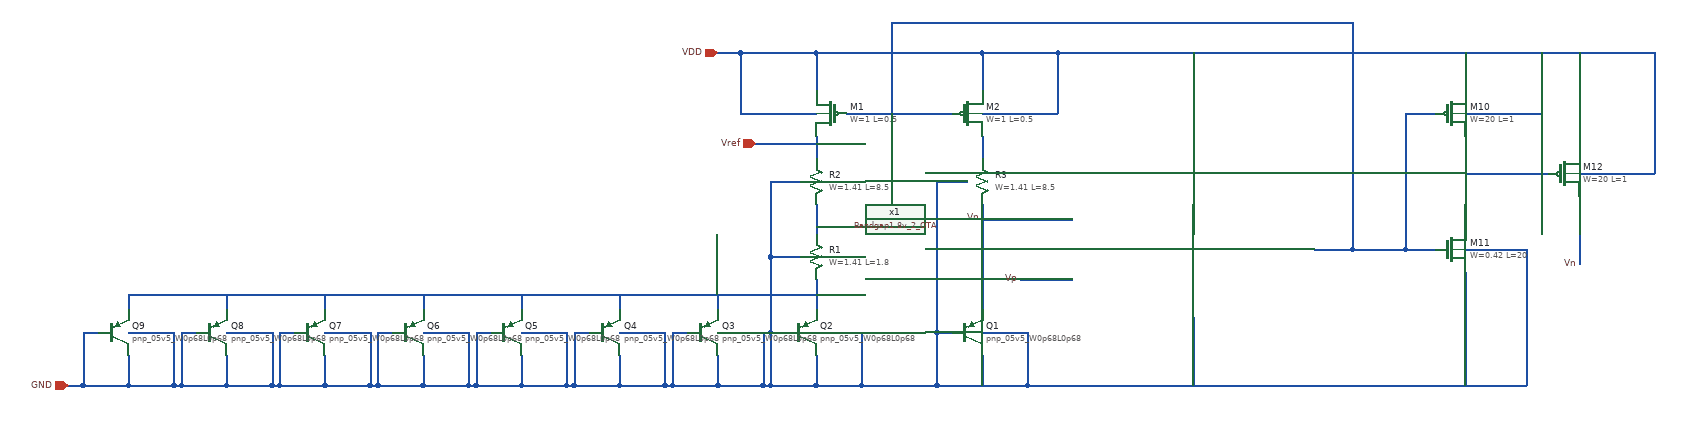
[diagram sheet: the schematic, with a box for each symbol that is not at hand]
v {xschem version=2.9.9 file_version=1.2 }
G {}
K {}
V {}
S {}
E {}
N -1770 -1250 -1630 -1250 { lab=#net1}
N -1590 -1330 -1590 -1280 { lab=VDD}
N -1810 -1330 -1590 -1330 { lab=VDD}
N -1810 -1330 -1810 -1280 { lab=VDD}
N -1590 -1250 -1490 -1250 { lab=VDD}
N -1490 -1330 -1490 -1250 { lab=VDD}
N -1590 -1330 -1490 -1330 { lab=VDD}
N -1910 -1250 -1810 -1250 { lab=VDD}
N -1910 -1330 -1910 -1250 { lab=VDD}
N -1910 -1330 -1810 -1330 { lab=VDD}
N -1590 -1220 -1590 -1190 { lab=#net2}
N -1810 -1220 -1810 -1190 { lab=xxx}
N -1810 -1130 -1810 -1090 { lab=Vp}
N -1590 -1130 -1590 -990 { lab=Vn}
N -1810 -1030 -1810 -990 { lab=#net3}
N -1590 -930 -1590 -890 { lab=GND}
N -1590 -960 -1530 -960 { lab=GND}
N -1530 -960 -1530 -890 { lab=GND}
N -1650 -960 -1630 -960 { lab=GND}
N -1650 -960 -1650 -890 { lab=GND}
N -1650 -890 -1530 -890 { lab=GND}
N -1810 -930 -1810 -890 { lab=GND}
N -1810 -890 -1750 -890 { lab=GND}
N -1750 -960 -1750 -890 { lab=GND}
N -1810 -960 -1750 -960 { lab=GND}
N -1870 -960 -1850 -960 { lab=GND}
N -1870 -960 -1870 -890 { lab=GND}
N -1870 -890 -1810 -890 { lab=GND}
N -1940 -930 -1940 -890 { lab=GND}
N -1940 -890 -1880 -890 { lab=GND}
N -1880 -960 -1880 -890 { lab=GND}
N -1940 -960 -1880 -960 { lab=GND}
N -2000 -960 -1980 -960 { lab=GND}
N -2000 -960 -2000 -890 { lab=GND}
N -2000 -890 -1940 -890 { lab=GND}
N -2070 -930 -2070 -890 { lab=GND}
N -2070 -890 -2010 -890 { lab=GND}
N -2010 -960 -2010 -890 { lab=GND}
N -2070 -960 -2010 -960 { lab=GND}
N -2130 -960 -2110 -960 { lab=GND}
N -2130 -960 -2130 -890 { lab=GND}
N -2130 -890 -2070 -890 { lab=GND}
N -2200 -930 -2200 -890 { lab=GND}
N -2200 -890 -2140 -890 { lab=GND}
N -2140 -960 -2140 -890 { lab=GND}
N -2200 -960 -2140 -960 { lab=GND}
N -2260 -960 -2240 -960 { lab=GND}
N -2260 -960 -2260 -890 { lab=GND}
N -2260 -890 -2200 -890 { lab=GND}
N -2330 -930 -2330 -890 { lab=GND}
N -2330 -890 -2270 -890 { lab=GND}
N -2270 -960 -2270 -890 { lab=GND}
N -2330 -960 -2270 -960 { lab=GND}
N -2390 -960 -2370 -960 { lab=GND}
N -2390 -960 -2390 -890 { lab=GND}
N -2390 -890 -2330 -890 { lab=GND}
N -2460 -930 -2460 -890 { lab=GND}
N -2460 -890 -2400 -890 { lab=GND}
N -2400 -960 -2400 -890 { lab=GND}
N -2460 -960 -2400 -960 { lab=GND}
N -2520 -960 -2500 -960 { lab=GND}
N -2520 -960 -2520 -890 { lab=GND}
N -2520 -890 -2460 -890 { lab=GND}
N -2590 -930 -2590 -890 { lab=GND}
N -2590 -890 -2530 -890 { lab=GND}
N -2530 -960 -2530 -890 { lab=GND}
N -2590 -960 -2530 -960 { lab=GND}
N -2650 -960 -2630 -960 { lab=GND}
N -2650 -960 -2650 -890 { lab=GND}
N -2650 -890 -2590 -890 { lab=GND}
N -2720 -930 -2720 -890 { lab=GND}
N -2720 -890 -2660 -890 { lab=GND}
N -2660 -960 -2660 -890 { lab=GND}
N -2720 -960 -2660 -960 { lab=GND}
N -2780 -960 -2760 -960 { lab=GND}
N -2780 -960 -2780 -890 { lab=GND}
N -2780 -890 -2720 -890 { lab=GND}
N -2720 -1010 -2720 -990 { lab=#net3}
N -2720 -1010 -1810 -1010 { lab=#net3}
N -1940 -1010 -1940 -990 { lab=#net3}
N -2070 -1010 -2070 -990 { lab=#net3}
N -2200 -1010 -2200 -990 { lab=#net3}
N -2330 -1010 -2330 -990 { lab=#net3}
N -2460 -1010 -2460 -990 { lab=#net3}
N -2590 -1010 -2590 -990 { lab=#net3}
N -1880 -890 -1870 -890 { lab=GND}
N -2010 -890 -2000 -890 { lab=GND}
N -2140 -890 -2130 -890 { lab=GND}
N -2270 -890 -2260 -890 { lab=GND}
N -2400 -890 -2390 -890 { lab=GND}
N -2530 -890 -2520 -890 { lab=GND}
N -2660 -890 -2650 -890 { lab=GND}
N -1870 -1060 -1830 -1060 { lab=GND}
N -1870 -1060 -1870 -960 { lab=GND}
N -1870 -1160 -1830 -1160 { lab=GND}
N -1870 -1160 -1870 -1060 { lab=GND}
N -1650 -1160 -1610 -1160 { lab=GND}
N -1650 -1160 -1650 -960 { lab=GND}
N -1750 -890 -1650 -890 { lab=GND}
N -1810 -1100 -1710 -1100 { lab=Vp}
N -1590 -1110 -1470 -1110 { lab=Vn}
N -1890 -1210 -1810 -1210 { lab=xxx}
N -1710 -1370 -1710 -1250 { lab=#net1}
N -1940 -1330 -1910 -1330 { lab=VDD}
N -1710 -1370 -1190 -1370 { lab=#net1}
N -950 -1220 -950 -1100 { lab=#net4}
N -1030 -1250 -990 -1250 { lab=#net1}
N -1030 -1250 -1030 -1070 { lab=#net1}
N -1030 -1070 -990 -1070 { lab=#net1}
N -950 -1040 -950 -890 { lab=GND}
N -950 -1070 -870 -1070 { lab=GND}
N -870 -1070 -870 -890 { lab=GND}
N -950 -1170 -840 -1170 { lab=#net4}
N -800 -1140 -800 -1050 { lab=Vn}
N -1100 -890 -870 -890 { lab=GND}
N -950 -1330 -950 -1280 { lab=VDD}
N -950 -1250 -850 -1250 { lab=VDD}
N -850 -1330 -850 -1250 { lab=VDD}
N -800 -1330 -800 -1200 { lab=VDD}
N -800 -1170 -700 -1170 { lab=VDD}
N -700 -1330 -700 -1170 { lab=VDD}
N -1080 -1330 -700 -1330 { lab=VDD}
N -1540 -1030 -1470 -1030 { lab=Vp}
N -1310 -980 -1310 -890 { lab=GND}
N -1310 -1330 -1310 -1160 { lab=VDD}
N -1490 -1330 -1080 -1330 { lab=VDD}
N -1530 -890 -1100 -890 { lab=GND}
N -1150 -1070 -1100 -1070 { lab=#net1}
N -1100 -1370 -1100 -1070 { lab=#net1}
N -1190 -1370 -1100 -1370 { lab=#net1}
N -1100 -1070 -1030 -1070 { lab=#net1}
N -2800 -890 -2780 -890 { lab=GND}
C {sky130_fd_pr/pfet_g5v0d10v5.sym} -1790 -1250 0 1 {name=M1
L=0.5
W=1
nf=1
mult=10
ad="'int((nf+1)/2) * W/nf * 0.29'" 
pd="'2*int((nf+1)/2) * (W/nf + 0.29)'"
as="'int((nf+2)/2) * W/nf * 0.29'" 
ps="'2*int((nf+2)/2) * (W/nf + 0.29)'"
nrd="'0.29 / W'" nrs="'0.29 / W'"
sa=0 sb=0 sd=0
model=pfet_g5v0d10v5
spiceprefix=X
}
C {sky130_fd_pr/pfet_g5v0d10v5.sym} -1610 -1250 0 0 {name=M2
L=0.5
W=1
nf=1
mult=10
ad="'int((nf+1)/2) * W/nf * 0.29'" 
pd="'2*int((nf+1)/2) * (W/nf + 0.29)'"
as="'int((nf+2)/2) * W/nf * 0.29'" 
ps="'2*int((nf+2)/2) * (W/nf + 0.29)'"
nrd="'0.29 / W'" nrs="'0.29 / W'"
sa=0 sb=0 sd=0
model=pfet_g5v0d10v5
spiceprefix=X
}
C {sky130_fd_pr/pnp_05v5.sym} -1610 -960 0 0 {name=Q1
model=pnp_05v5_W0p68L0p68
spiceprefix=X
}
C {sky130_fd_pr/pnp_05v5.sym} -1830 -960 0 0 {name=Q2
model=pnp_05v5_W0p68L0p68
spiceprefix=X
}
C {sky130_fd_pr/pnp_05v5.sym} -1960 -960 0 0 {name=Q3
model=pnp_05v5_W0p68L0p68
spiceprefix=X
}
C {sky130_fd_pr/pnp_05v5.sym} -2090 -960 0 0 {name=Q4
model=pnp_05v5_W0p68L0p68
spiceprefix=X
}
C {sky130_fd_pr/pnp_05v5.sym} -2220 -960 0 0 {name=Q5
model=pnp_05v5_W0p68L0p68
spiceprefix=X
}
C {sky130_fd_pr/pnp_05v5.sym} -2350 -960 0 0 {name=Q6
model=pnp_05v5_W0p68L0p68
spiceprefix=X
}
C {sky130_fd_pr/pnp_05v5.sym} -2480 -960 0 0 {name=Q7
model=pnp_05v5_W0p68L0p68
spiceprefix=X
}
C {sky130_fd_pr/pnp_05v5.sym} -2610 -960 0 0 {name=Q8
model=pnp_05v5_W0p68L0p68
spiceprefix=X
}
C {sky130_fd_pr/pnp_05v5.sym} -2740 -960 0 0 {name=Q9
model=pnp_05v5_W0p68L0p68
spiceprefix=X
}
C {devices/lab_pin.sym} -1710 -1100 0 1 {name=l3 sig_type=std_logic lab=Vp}
C {sky130_fd_pr/res_xhigh_po_1p41.sym} -1810 -1060 0 0 {name=R1
W=1.41
L=1.8
model=res_xhigh_po_1p41
spiceprefix=X
mult=1}
C {sky130_fd_pr/res_xhigh_po_1p41.sym} -1810 -1160 0 0 {name=R2
W=1.41
L=8.5
model=res_xhigh_po_1p41
spiceprefix=X
mult=1}
C {sky130_fd_pr/res_xhigh_po_1p41.sym} -1590 -1160 0 0 {name=R3
W=1.41
L=8.5
model=res_xhigh_po_1p41
spiceprefix=X
mult=1}
C {sky130_fd_pr/pfet_g5v0d10v5.sym} -970 -1250 0 0 {name=M10
L=1
W=20
nf=1
mult=2
ad="'int((nf+1)/2) * W/nf * 0.29'" 
pd="'2*int((nf+1)/2) * (W/nf + 0.29)'"
as="'int((nf+2)/2) * W/nf * 0.29'" 
ps="'2*int((nf+2)/2) * (W/nf + 0.29)'"
nrd="'0.29 / W'" nrs="'0.29 / W'"
sa=0 sb=0 sd=0
model=pfet_g5v0d10v5
spiceprefix=X
}
C {sky130_fd_pr/nfet_g5v0d10v5.sym} -970 -1070 0 0 {name=M11
L=20
W=0.42
nf=1
mult=1
ad="'int((nf+1)/2) * W/nf * 0.29'" 
pd="'2*int((nf+1)/2) * (W/nf + 0.29)'"
as="'int((nf+2)/2) * W/nf * 0.29'" 
ps="'2*int((nf+2)/2) * (W/nf + 0.29)'"
nrd="'0.29 / W'" nrs="'0.29 / W'"
sa=0 sb=0 sd=0
model=nfet_g5v0d10v5
spiceprefix=X
}
C {sky130_fd_pr/pfet_g5v0d10v5.sym} -820 -1170 0 0 {name=M12
L=1
W=20
nf=1
mult=2
ad="'int((nf+1)/2) * W/nf * 0.29'" 
pd="'2*int((nf+1)/2) * (W/nf + 0.29)'"
as="'int((nf+2)/2) * W/nf * 0.29'" 
ps="'2*int((nf+2)/2) * (W/nf + 0.29)'"
nrd="'0.29 / W'" nrs="'0.29 / W'"
sa=0 sb=0 sd=0
model=pfet_g5v0d10v5
spiceprefix=X
}
C {devices/lab_pin.sym} -1590 -1110 0 0 {name=l4 sig_type=std_logic lab=Vn}
C {devices/lab_pin.sym} -800 -1050 0 0 {name=l6 sig_type=std_logic lab=Vn}
C {/home/eslam/Analog_blocks/Analog_Blocks/Bandgap/Schematics/BGR1.8v_2/Bandgap1.8v_2_OTA.sym} -1310 -1070 0 0 {name=x1}
C {devices/lab_pin.sym} -1540 -1030 0 0 {name=l7 sig_type=std_logic lab=Vp}
C {devices/ipin.sym} -1940 -1330 0 0 {name=p1 lab=VDD}
C {devices/ipin.sym} -2800 -890 0 0 {name=p2 lab=GND}
C {devices/opin.sym} -1890 -1210 0 1 {name=p3 lab=Vref}
